VERSION 5.7 ;
BUSBITCHARS "[]" ;
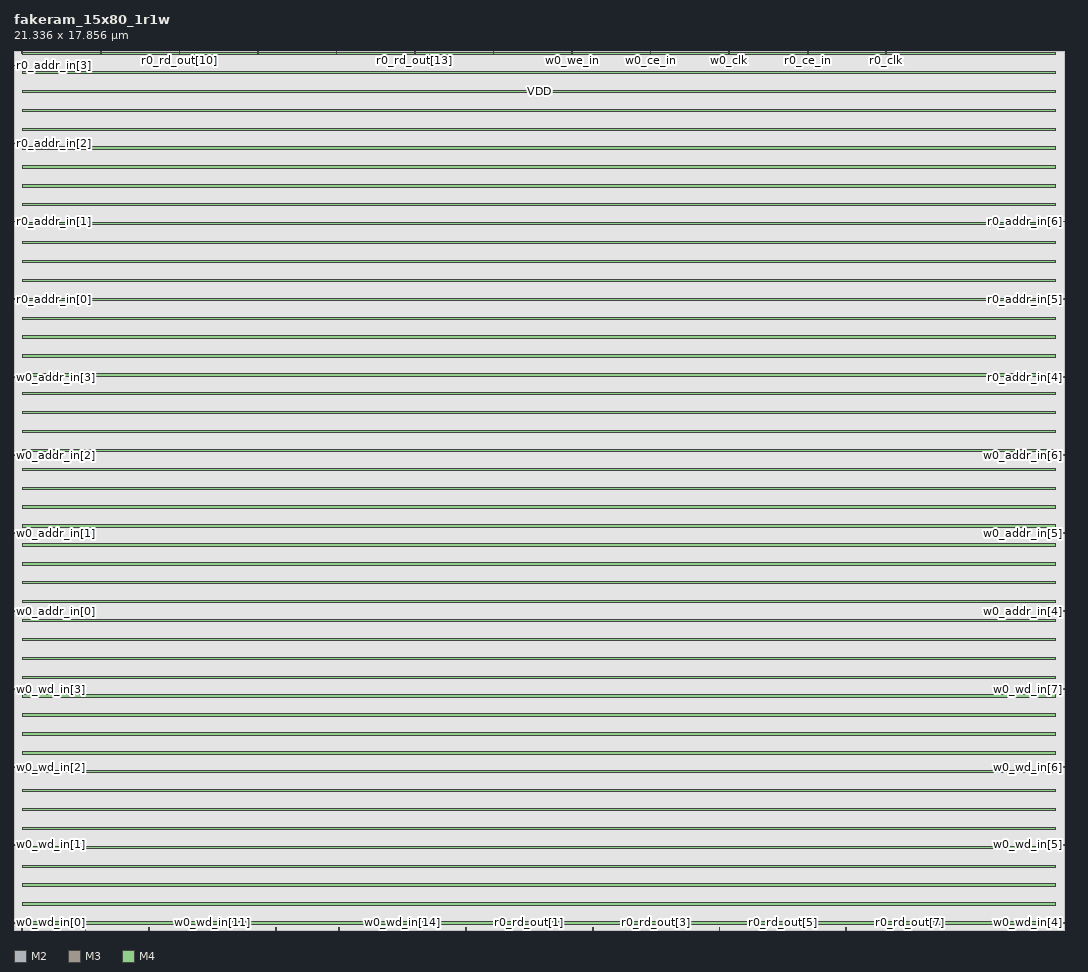
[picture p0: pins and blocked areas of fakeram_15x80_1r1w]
MACRO fakeram_15x80_1r1w
  FOREIGN fakeram_15x80_1r1w 0 0 ;
  SYMMETRY X Y R90 ;
  SIZE 21.336 BY 17.856 ;
  CLASS BLOCK ;
  PIN w0_wd_in[0]
    DIRECTION INPUT ;
    USE SIGNAL ;
    SHAPE ABUTMENT ;
    PORT
      LAYER M2 ;
      RECT 0.000 0.138 0.036 0.150 ;
    END
  END w0_wd_in[0]
  PIN w0_wd_in[1]
    DIRECTION INPUT ;
    USE SIGNAL ;
    SHAPE ABUTMENT ;
    PORT
      LAYER M2 ;
      RECT 0.000 1.722 0.036 1.734 ;
    END
  END w0_wd_in[1]
  PIN w0_wd_in[2]
    DIRECTION INPUT ;
    USE SIGNAL ;
    SHAPE ABUTMENT ;
    PORT
      LAYER M2 ;
      RECT 0.000 3.306 0.036 3.318 ;
    END
  END w0_wd_in[2]
  PIN w0_wd_in[3]
    DIRECTION INPUT ;
    USE SIGNAL ;
    SHAPE ABUTMENT ;
    PORT
      LAYER M2 ;
      RECT 0.000 4.890 0.036 4.902 ;
    END
  END w0_wd_in[3]
  PIN w0_wd_in[4]
    DIRECTION INPUT ;
    USE SIGNAL ;
    SHAPE ABUTMENT ;
    PORT
      LAYER M2 ;
      RECT 21.300 0.138 21.336 0.150 ;
    END
  END w0_wd_in[4]
  PIN w0_wd_in[5]
    DIRECTION INPUT ;
    USE SIGNAL ;
    SHAPE ABUTMENT ;
    PORT
      LAYER M2 ;
      RECT 21.300 1.722 21.336 1.734 ;
    END
  END w0_wd_in[5]
  PIN w0_wd_in[6]
    DIRECTION INPUT ;
    USE SIGNAL ;
    SHAPE ABUTMENT ;
    PORT
      LAYER M2 ;
      RECT 21.300 3.306 21.336 3.318 ;
    END
  END w0_wd_in[6]
  PIN w0_wd_in[7]
    DIRECTION INPUT ;
    USE SIGNAL ;
    SHAPE ABUTMENT ;
    PORT
      LAYER M2 ;
      RECT 21.300 4.890 21.336 4.902 ;
    END
  END w0_wd_in[7]
  PIN w0_wd_in[8]
    DIRECTION INPUT ;
    USE SIGNAL ;
    SHAPE ABUTMENT ;
    PORT
      LAYER M3 ;
      RECT 0.161 0.000 0.175 0.042 ;
    END
  END w0_wd_in[8]
  PIN w0_wd_in[9]
    DIRECTION INPUT ;
    USE SIGNAL ;
    SHAPE ABUTMENT ;
    PORT
      LAYER M3 ;
      RECT 1.449 0.000 1.463 0.042 ;
    END
  END w0_wd_in[9]
  PIN w0_wd_in[10]
    DIRECTION INPUT ;
    USE SIGNAL ;
    SHAPE ABUTMENT ;
    PORT
      LAYER M3 ;
      RECT 2.737 0.000 2.751 0.042 ;
    END
  END w0_wd_in[10]
  PIN w0_wd_in[11]
    DIRECTION INPUT ;
    USE SIGNAL ;
    SHAPE ABUTMENT ;
    PORT
      LAYER M3 ;
      RECT 4.025 0.000 4.039 0.042 ;
    END
  END w0_wd_in[11]
  PIN w0_wd_in[12]
    DIRECTION INPUT ;
    USE SIGNAL ;
    SHAPE ABUTMENT ;
    PORT
      LAYER M3 ;
      RECT 5.313 0.000 5.327 0.042 ;
    END
  END w0_wd_in[12]
  PIN w0_wd_in[13]
    DIRECTION INPUT ;
    USE SIGNAL ;
    SHAPE ABUTMENT ;
    PORT
      LAYER M3 ;
      RECT 6.601 0.000 6.615 0.042 ;
    END
  END w0_wd_in[13]
  PIN w0_wd_in[14]
    DIRECTION INPUT ;
    USE SIGNAL ;
    SHAPE ABUTMENT ;
    PORT
      LAYER M3 ;
      RECT 7.889 0.000 7.903 0.042 ;
    END
  END w0_wd_in[14]
  PIN r0_rd_out[0]
    DIRECTION OUTPUT ;
    USE SIGNAL ;
    SHAPE ABUTMENT ;
    PORT
      LAYER M3 ;
      RECT 9.177 0.000 9.191 0.042 ;
    END
  END r0_rd_out[0]
  PIN r0_rd_out[1]
    DIRECTION OUTPUT ;
    USE SIGNAL ;
    SHAPE ABUTMENT ;
    PORT
      LAYER M3 ;
      RECT 10.465 0.000 10.479 0.042 ;
    END
  END r0_rd_out[1]
  PIN r0_rd_out[2]
    DIRECTION OUTPUT ;
    USE SIGNAL ;
    SHAPE ABUTMENT ;
    PORT
      LAYER M3 ;
      RECT 11.753 0.000 11.767 0.042 ;
    END
  END r0_rd_out[2]
  PIN r0_rd_out[3]
    DIRECTION OUTPUT ;
    USE SIGNAL ;
    SHAPE ABUTMENT ;
    PORT
      LAYER M3 ;
      RECT 13.041 0.000 13.055 0.042 ;
    END
  END r0_rd_out[3]
  PIN r0_rd_out[4]
    DIRECTION OUTPUT ;
    USE SIGNAL ;
    SHAPE ABUTMENT ;
    PORT
      LAYER M3 ;
      RECT 14.329 0.000 14.343 0.042 ;
    END
  END r0_rd_out[4]
  PIN r0_rd_out[5]
    DIRECTION OUTPUT ;
    USE SIGNAL ;
    SHAPE ABUTMENT ;
    PORT
      LAYER M3 ;
      RECT 15.617 0.000 15.631 0.042 ;
    END
  END r0_rd_out[5]
  PIN r0_rd_out[6]
    DIRECTION OUTPUT ;
    USE SIGNAL ;
    SHAPE ABUTMENT ;
    PORT
      LAYER M3 ;
      RECT 16.905 0.000 16.919 0.042 ;
    END
  END r0_rd_out[6]
  PIN r0_rd_out[7]
    DIRECTION OUTPUT ;
    USE SIGNAL ;
    SHAPE ABUTMENT ;
    PORT
      LAYER M3 ;
      RECT 18.193 0.000 18.207 0.042 ;
    END
  END r0_rd_out[7]
  PIN r0_rd_out[8]
    DIRECTION OUTPUT ;
    USE SIGNAL ;
    SHAPE ABUTMENT ;
    PORT
      LAYER M3 ;
      RECT 0.161 17.814 0.175 17.856 ;
    END
  END r0_rd_out[8]
  PIN r0_rd_out[9]
    DIRECTION OUTPUT ;
    USE SIGNAL ;
    SHAPE ABUTMENT ;
    PORT
      LAYER M3 ;
      RECT 1.757 17.814 1.771 17.856 ;
    END
  END r0_rd_out[9]
  PIN r0_rd_out[10]
    DIRECTION OUTPUT ;
    USE SIGNAL ;
    SHAPE ABUTMENT ;
    PORT
      LAYER M3 ;
      RECT 3.353 17.814 3.367 17.856 ;
    END
  END r0_rd_out[10]
  PIN r0_rd_out[11]
    DIRECTION OUTPUT ;
    USE SIGNAL ;
    SHAPE ABUTMENT ;
    PORT
      LAYER M3 ;
      RECT 4.949 17.814 4.963 17.856 ;
    END
  END r0_rd_out[11]
  PIN r0_rd_out[12]
    DIRECTION OUTPUT ;
    USE SIGNAL ;
    SHAPE ABUTMENT ;
    PORT
      LAYER M3 ;
      RECT 6.545 17.814 6.559 17.856 ;
    END
  END r0_rd_out[12]
  PIN r0_rd_out[13]
    DIRECTION OUTPUT ;
    USE SIGNAL ;
    SHAPE ABUTMENT ;
    PORT
      LAYER M3 ;
      RECT 8.141 17.814 8.155 17.856 ;
    END
  END r0_rd_out[13]
  PIN r0_rd_out[14]
    DIRECTION OUTPUT ;
    USE SIGNAL ;
    SHAPE ABUTMENT ;
    PORT
      LAYER M3 ;
      RECT 9.737 17.814 9.751 17.856 ;
    END
  END r0_rd_out[14]
  PIN w0_addr_in[0]
    DIRECTION INPUT ;
    USE SIGNAL ;
    SHAPE ABUTMENT ;
    PORT
      LAYER M2 ;
      RECT 0.000 6.474 0.036 6.486 ;
    END
  END w0_addr_in[0]
  PIN w0_addr_in[1]
    DIRECTION INPUT ;
    USE SIGNAL ;
    SHAPE ABUTMENT ;
    PORT
      LAYER M2 ;
      RECT 0.000 8.058 0.036 8.070 ;
    END
  END w0_addr_in[1]
  PIN w0_addr_in[2]
    DIRECTION INPUT ;
    USE SIGNAL ;
    SHAPE ABUTMENT ;
    PORT
      LAYER M2 ;
      RECT 0.000 9.642 0.036 9.654 ;
    END
  END w0_addr_in[2]
  PIN w0_addr_in[3]
    DIRECTION INPUT ;
    USE SIGNAL ;
    SHAPE ABUTMENT ;
    PORT
      LAYER M2 ;
      RECT 0.000 11.226 0.036 11.238 ;
    END
  END w0_addr_in[3]
  PIN w0_addr_in[4]
    DIRECTION INPUT ;
    USE SIGNAL ;
    SHAPE ABUTMENT ;
    PORT
      LAYER M2 ;
      RECT 21.300 6.474 21.336 6.486 ;
    END
  END w0_addr_in[4]
  PIN w0_addr_in[5]
    DIRECTION INPUT ;
    USE SIGNAL ;
    SHAPE ABUTMENT ;
    PORT
      LAYER M2 ;
      RECT 21.300 8.058 21.336 8.070 ;
    END
  END w0_addr_in[5]
  PIN w0_addr_in[6]
    DIRECTION INPUT ;
    USE SIGNAL ;
    SHAPE ABUTMENT ;
    PORT
      LAYER M2 ;
      RECT 21.300 9.642 21.336 9.654 ;
    END
  END w0_addr_in[6]
  PIN r0_addr_in[0]
    DIRECTION INPUT ;
    USE SIGNAL ;
    SHAPE ABUTMENT ;
    PORT
      LAYER M2 ;
      RECT 0.000 12.810 0.036 12.822 ;
    END
  END r0_addr_in[0]
  PIN r0_addr_in[1]
    DIRECTION INPUT ;
    USE SIGNAL ;
    SHAPE ABUTMENT ;
    PORT
      LAYER M2 ;
      RECT 0.000 14.394 0.036 14.406 ;
    END
  END r0_addr_in[1]
  PIN r0_addr_in[2]
    DIRECTION INPUT ;
    USE SIGNAL ;
    SHAPE ABUTMENT ;
    PORT
      LAYER M2 ;
      RECT 0.000 15.978 0.036 15.990 ;
    END
  END r0_addr_in[2]
  PIN r0_addr_in[3]
    DIRECTION INPUT ;
    USE SIGNAL ;
    SHAPE ABUTMENT ;
    PORT
      LAYER M2 ;
      RECT 0.000 17.562 0.036 17.574 ;
    END
  END r0_addr_in[3]
  PIN r0_addr_in[4]
    DIRECTION INPUT ;
    USE SIGNAL ;
    SHAPE ABUTMENT ;
    PORT
      LAYER M2 ;
      RECT 21.300 11.226 21.336 11.238 ;
    END
  END r0_addr_in[4]
  PIN r0_addr_in[5]
    DIRECTION INPUT ;
    USE SIGNAL ;
    SHAPE ABUTMENT ;
    PORT
      LAYER M2 ;
      RECT 21.300 12.810 21.336 12.822 ;
    END
  END r0_addr_in[5]
  PIN r0_addr_in[6]
    DIRECTION INPUT ;
    USE SIGNAL ;
    SHAPE ABUTMENT ;
    PORT
      LAYER M2 ;
      RECT 21.300 14.394 21.336 14.406 ;
    END
  END r0_addr_in[6]
  PIN w0_we_in
    DIRECTION INPUT ;
    USE SIGNAL ;
    SHAPE ABUTMENT ;
    PORT
      LAYER M3 ;
      RECT 11.333 17.814 11.347 17.856 ;
    END
  END w0_we_in
  PIN w0_ce_in
    DIRECTION INPUT ;
    USE SIGNAL ;
    SHAPE ABUTMENT ;
    PORT
      LAYER M3 ;
      RECT 12.929 17.814 12.943 17.856 ;
    END
  END w0_ce_in
  PIN w0_clk
    DIRECTION INPUT ;
    USE SIGNAL ;
    SHAPE ABUTMENT ;
    PORT
      LAYER M3 ;
      RECT 14.525 17.814 14.539 17.856 ;
    END
  END w0_clk
  PIN r0_ce_in
    DIRECTION INPUT ;
    USE SIGNAL ;
    SHAPE ABUTMENT ;
    PORT
      LAYER M3 ;
      RECT 16.121 17.814 16.135 17.856 ;
    END
  END r0_ce_in
  PIN r0_clk
    DIRECTION INPUT ;
    USE SIGNAL ;
    SHAPE ABUTMENT ;
    PORT
      LAYER M3 ;
      RECT 17.717 17.814 17.731 17.856 ;
    END
  END r0_clk
  PIN VSS
    DIRECTION INOUT ;
    USE GROUND ;
    PORT
      LAYER M4 ;
      RECT 0.168 0.120 21.168 0.168 ;
      RECT 0.168 0.504 21.168 0.552 ;
      RECT 0.168 0.888 21.168 0.936 ;
      RECT 0.168 1.272 21.168 1.320 ;
      RECT 0.168 1.656 21.168 1.704 ;
      RECT 0.168 2.040 21.168 2.088 ;
      RECT 0.168 2.424 21.168 2.472 ;
      RECT 0.168 2.808 21.168 2.856 ;
      RECT 0.168 3.192 21.168 3.240 ;
      RECT 0.168 3.576 21.168 3.624 ;
      RECT 0.168 3.960 21.168 4.008 ;
      RECT 0.168 4.344 21.168 4.392 ;
      RECT 0.168 4.728 21.168 4.776 ;
      RECT 0.168 5.112 21.168 5.160 ;
      RECT 0.168 5.496 21.168 5.544 ;
      RECT 0.168 5.880 21.168 5.928 ;
      RECT 0.168 6.264 21.168 6.312 ;
      RECT 0.168 6.648 21.168 6.696 ;
      RECT 0.168 7.032 21.168 7.080 ;
      RECT 0.168 7.416 21.168 7.464 ;
      RECT 0.168 7.800 21.168 7.848 ;
      RECT 0.168 8.184 21.168 8.232 ;
      RECT 0.168 8.568 21.168 8.616 ;
      RECT 0.168 8.952 21.168 9.000 ;
      RECT 0.168 9.336 21.168 9.384 ;
      RECT 0.168 9.720 21.168 9.768 ;
      RECT 0.168 10.104 21.168 10.152 ;
      RECT 0.168 10.488 21.168 10.536 ;
      RECT 0.168 10.872 21.168 10.920 ;
      RECT 0.168 11.256 21.168 11.304 ;
      RECT 0.168 11.640 21.168 11.688 ;
      RECT 0.168 12.024 21.168 12.072 ;
      RECT 0.168 12.408 21.168 12.456 ;
      RECT 0.168 12.792 21.168 12.840 ;
      RECT 0.168 13.176 21.168 13.224 ;
      RECT 0.168 13.560 21.168 13.608 ;
      RECT 0.168 13.944 21.168 13.992 ;
      RECT 0.168 14.328 21.168 14.376 ;
      RECT 0.168 14.712 21.168 14.760 ;
      RECT 0.168 15.096 21.168 15.144 ;
      RECT 0.168 15.480 21.168 15.528 ;
      RECT 0.168 15.864 21.168 15.912 ;
      RECT 0.168 16.248 21.168 16.296 ;
      RECT 0.168 16.632 21.168 16.680 ;
      RECT 0.168 17.016 21.168 17.064 ;
      RECT 0.168 17.400 21.168 17.448 ;
      RECT 0.168 17.784 21.168 17.832 ;
    END
  END VSS
  PIN VDD
    DIRECTION INOUT ;
    USE POWER ;
    PORT
      LAYER M4 ;
      RECT 0.168 0.120 21.168 0.168 ;
      RECT 0.168 0.504 21.168 0.552 ;
      RECT 0.168 0.888 21.168 0.936 ;
      RECT 0.168 1.272 21.168 1.320 ;
      RECT 0.168 1.656 21.168 1.704 ;
      RECT 0.168 2.040 21.168 2.088 ;
      RECT 0.168 2.424 21.168 2.472 ;
      RECT 0.168 2.808 21.168 2.856 ;
      RECT 0.168 3.192 21.168 3.240 ;
      RECT 0.168 3.576 21.168 3.624 ;
      RECT 0.168 3.960 21.168 4.008 ;
      RECT 0.168 4.344 21.168 4.392 ;
      RECT 0.168 4.728 21.168 4.776 ;
      RECT 0.168 5.112 21.168 5.160 ;
      RECT 0.168 5.496 21.168 5.544 ;
      RECT 0.168 5.880 21.168 5.928 ;
      RECT 0.168 6.264 21.168 6.312 ;
      RECT 0.168 6.648 21.168 6.696 ;
      RECT 0.168 7.032 21.168 7.080 ;
      RECT 0.168 7.416 21.168 7.464 ;
      RECT 0.168 7.800 21.168 7.848 ;
      RECT 0.168 8.184 21.168 8.232 ;
      RECT 0.168 8.568 21.168 8.616 ;
      RECT 0.168 8.952 21.168 9.000 ;
      RECT 0.168 9.336 21.168 9.384 ;
      RECT 0.168 9.720 21.168 9.768 ;
      RECT 0.168 10.104 21.168 10.152 ;
      RECT 0.168 10.488 21.168 10.536 ;
      RECT 0.168 10.872 21.168 10.920 ;
      RECT 0.168 11.256 21.168 11.304 ;
      RECT 0.168 11.640 21.168 11.688 ;
      RECT 0.168 12.024 21.168 12.072 ;
      RECT 0.168 12.408 21.168 12.456 ;
      RECT 0.168 12.792 21.168 12.840 ;
      RECT 0.168 13.176 21.168 13.224 ;
      RECT 0.168 13.560 21.168 13.608 ;
      RECT 0.168 13.944 21.168 13.992 ;
      RECT 0.168 14.328 21.168 14.376 ;
      RECT 0.168 14.712 21.168 14.760 ;
      RECT 0.168 15.096 21.168 15.144 ;
      RECT 0.168 15.480 21.168 15.528 ;
      RECT 0.168 15.864 21.168 15.912 ;
      RECT 0.168 16.248 21.168 16.296 ;
      RECT 0.168 16.632 21.168 16.680 ;
      RECT 0.168 17.016 21.168 17.064 ;
      RECT 0.168 17.400 21.168 17.448 ;
      RECT 0.168 17.784 21.168 17.832 ;
    END
  END VDD
  OBS
    LAYER M1 ;
    RECT 0 0 21.336 17.856 ;
    LAYER M2 ;
    RECT 0 0 21.336 17.856 ;
    LAYER M3 ;
    RECT 0 0 21.336 17.856 ;
    LAYER M4 ;
    RECT 0 0 21.336 17.856 ;
  END
END fakeram_15x80_1r1w

END LIBRARY
